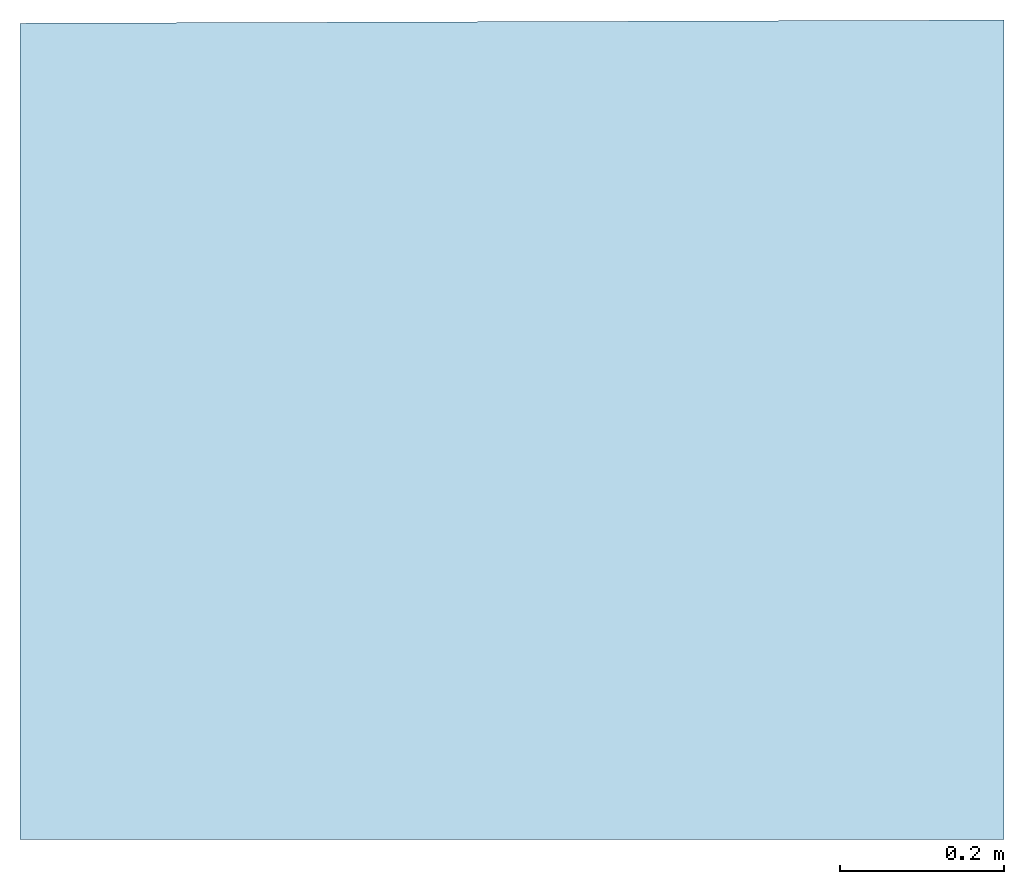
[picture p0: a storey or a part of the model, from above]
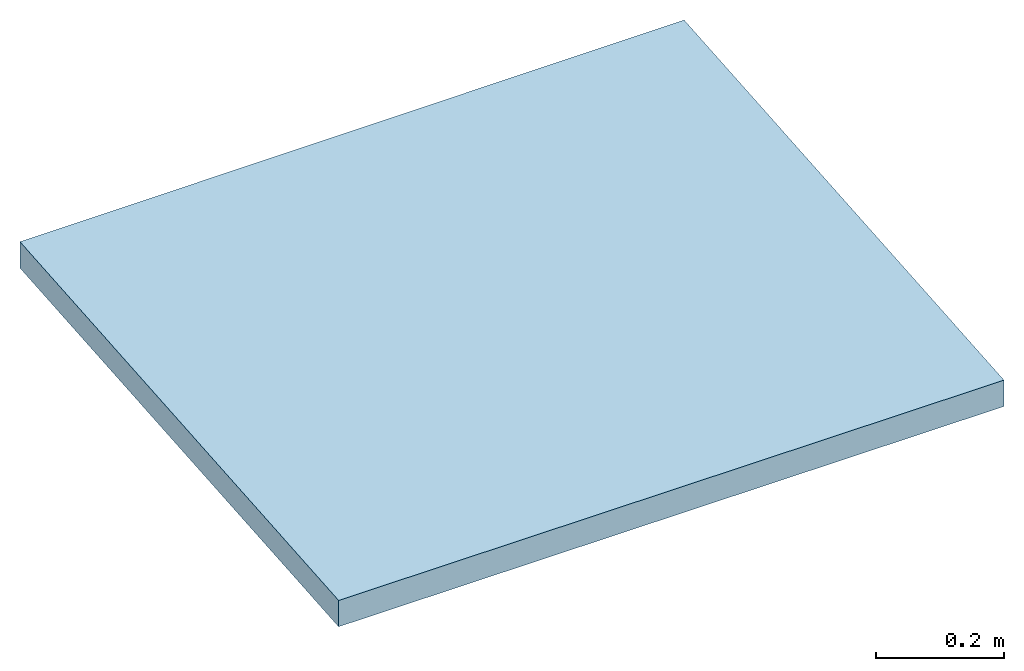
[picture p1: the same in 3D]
Properties of the parts of a building model (IFC2X3)

# File
Description: ViewDefinition [CoordinationView_V2.0], Option [Elements to export: Visible elements (on all stories)], Option [Partial Structure Display: Entire Model], Option [IFC Domain: All], Option [Structural Function: All Elements], Option [Convert Grid elements: On], Option [Convert IFC Annotations and Archicad 2D elements: Off], Option [Convert 2D symbols of Doors and Windows: Off], Option [Export geometries that Participates in Collision Detection only: Off], Option [Split complex elements: Off], Option [Material Preservation: Explode where necessary], Option [Elements in Solid Element Operations: Extruded/revolved], Option [Elements with junctions: Extruded/revolved without junctions], Option [IFC Model position: Survey Point and Project Origin], Option [Curtain Wall export mode: Container Element], Option [Railing export mode: Single Element], Option [Stair export mode: Container Element], Option [Properties To Export: All properties], Option [Space containment: Off], Option [Geometry to type objects: Off], Option [Element Properties: Off], Option [Building Material Properties: Off], Option [Element Parameters: Off], Option [Component Parameters: Off], Option [IFC Base Quantities: Off], Option [Door Window Parameters: On], Option [IFC Space boundaries: Off], Option [Archicad Zone Categories as IFC Space classification data: Off], Option [Element Classifications: Off]
File name: D:\Escritório\Mirela\MINISTERIO DA SAUDE\UBS\UBS PORTE 2\PDF ENTREGA 14.10.24\UBS PORTE 2 - R01.ifc
Time: 2024-10-14T22:08:18
Author: EQUIPE DE ARQUITETURA SAES
Organization: Building Designer Office
Written by: DDS_IFC v3.0
Made in: IFC file generated by Graphisoft Archicad 26.0.0 INT FULL Windows version (IFC add-on version: 4019 INT FULL).
Authorization: EQUIPE DE ARQUITETURA SAES

# IfcProject, UBS - PORTE II
Description: -; Phase: PROJETO EXECUTIVO

# IfcSite, Site
RefLatitude: 24, 28, 0, 0; RefLongitude: 54, 25, 0, 0; RefElevation: 0 mm

# IfcBuildingStorey (4)
In: Building
Name | LongName | Elevation (mm)
TÉRREO | TÉRREO | 150
COBERTURA | COBERTURA | 3650
PLATIBANDA | PLATIBANDA | 5750
NÍVEL DA RUA |  | 0

# IfcBeam: Concreto 200 x 950 (3)
In: PLATIBANDA
Material: Concreto
Pset_BeamCommon - Reference: Viga C-30 - Seção Retangular 20 X 95; IsExternal: yes; LoadBearing: yes
AltoQi_Eberick_Cargas - Cargas de parede (G2): 0; Adicional (G2): 0; Solo (S): 0; Acidental (Q): 0; Água (A): 0; Subpressão (AS): 0
AltoQi_Eberick_Elemento - Elemento: Viga; Tipo: retangular; Seção_bw: 200 mm; Seção_h: 950 mm; Elevação: 0 mm; Taxa de armadura: 0.16 %
AltoQi_Eberick_Padrão - Ambiente: Externo; Cobrimento: 30 mm; Classe de concreto: C-30
AC_Pset_RenovationAndPhasing - Renovation Status: Existing
Pset_ConcreteElementGeneral - EnvironmentalClass: 2; ConstructionType: InSitu

# IfcBeam: Railing Type (80)
In: TÉRREO
AC_Pset_RenovationAndPhasing - Renovation Status: Existing

# IfcBuildingElementPart (341)
In: TÉRREO
Name | Material
8 x Vidro | Vidro
8 x 
8 x _METAL | _METAL
285 x _GRANITO | _GRANITO
20 x _REBOCO | _REBOCO
10 x _ALVENARIA | _ALVENARIA
_PISO | _PISO
_CONCRETO | _CONCRETO

# IfcBuildingElementProxy: Bancada Seca 01 500 x 200 (2)
In: TÉRREO
Material: _GRANITO
AC_Pset_RenovationAndPhasing - Renovation Status: Existing
Name | Description
BPC.200d-Escovodromo | Bancada em granito 2,00x0,50m, com duas cubas cerâmica oval.
BPC.100e-Escovodromo | Bancada em granito 1,00x0,50m, com uma cubas cerâmica oval.

# IfcBuildingElementProxy: Basin 26 (16)
In: TÉRREO
AC_Pset_RenovationAndPhasing - Renovation Status: Existing
Name | Description
15 x LV01 | Lavatório com coluna suspensa em louça, cor branco, com acabamento em coluna suspensa. Incluso válvula de metal cromado e sifão flexível em PVC.
LV.02 | Lavatório Infantil com coluna suspensa em louça, cor branco. Com acabamento em coluna suspensa. Incluso válvula de metal cromado e sifão flexível em PVC.

# IfcBuildingElementProxy: Blocks_Banco Perfurado_F03652PT(2), BC01
In: TÉRREO
Description: Banco articulado nos banheiros adaptados, com estrutura em aço inox, assento em polipropileno na cor branco, fixado na parede com sistema de travamento na vertical, dimensão 70cm x 45cm, com estrutura que suporte até 150kg.
AC_Pset_RenovationAndPhasing - Renovation Status: Existing

# IfcBuildingElementProxy: Fire-Products_Bosch_Sounders (2)
In: TÉRREO
Description: Botão de emergência, item de acessibilidade para banheiros.
AC_Pset_RenovationAndPhasing - Renovation Status: Existing

# IfcBuildingElementProxy: Fire-Products_Bosch_Sounders(3) (4)
In: TÉRREO
Description: Botão de emergência, item de acessibilidade para banheiros.
AC_Pset_RenovationAndPhasing - Renovation Status: Existing

# IfcBuildingElementProxy: Grab Bar 26 (26)
In: TÉRREO
AC_Pset_RenovationAndPhasing - Renovation Status: Existing
Name | Description
10 x BA80 | Barra de apoio, reta, fixa, em aço inox, l=80cm, com diâmetro de empunhadura de 30mm. Deverão ser instaladas nos banheiros PCD como suporte para o uso dos equipamentos.
5 x BA70 | Barra de apoio, reta, fixa, em aço inox, l=70cm, com diâmetro de empunhadura de 30mm. Deverão ser instaladas nos banheiros PCD como suporte para o uso dos equipamentos.
10 x BA40 | Barra de apoio, reta, fixa, em aço inox, l=40cm, com diâmetro de empunhadura de 30mm.
BA60 | Barra de apoio, reta, fixa, em aço inox, l=60cm, com diâmetro de empunhadura de 30mm.

# IfcBuildingElementProxy: Interruptor Elétrico BRA 26 (86)
In: TÉRREO
AC_Pset_RenovationAndPhasing - Renovation Status: Existing

# IfcBuildingElementProxy: Interruptor Elétrico BRA 26(1) (120)
In: TÉRREO
AC_Pset_RenovationAndPhasing - Renovation Status: Existing

# IfcBuildingElementProxy: Rectangular Floor Drain 26 (21)
In: TÉRREO
Description: Ralo sanfonado, dimensões 15 x 15cm com tampa escamoteável.
AC_Pset_RenovationAndPhasing - Renovation Status: Existing

# IfcBuildingElementProxy: Sanitary_Accessories_Cosmic_ARCHITECT-Hinged-Grab-Bar(2), BAR70
In: TÉRREO
Description: Barra de apoio, reta, articulável, em aço inox, l=70cm, com diâmetro de empunhadura de 30mm.
AC_Pset_RenovationAndPhasing - Renovation Status: Existing

# IfcBuildingElementProxy: Tap 26 (27)
In: TÉRREO
Description: Torneira de mesa, acionamento de pressão, acabamento e acessórios para fixação e instalação cromados.
Pset_ManufacturerTypeInformation - Manufacturer: Deca Vogue Plus, L510; ou similar de qualidade igual ou superior
AC_Pset_RenovationAndPhasing - Renovation Status: Existing

# IfcBuildingElementProxy: Various Structures - 2 Segments - 400 x 200 x 100 (80+20), x
In: TÉRREO
Description: Bancada em granito 1,60x0,60m, com uma cuba em inox retangular e uma cuba em cerâmica redonda.
AC_Pset_RenovationAndPhasing - Renovation Status: Existing

# IfcBuildingElementProxy: Various Structures - 2 Segments - 600 x 200 x 1250 (20+1230), X
In: TÉRREO
Description: Bancada em granito 2,50x0,60m, com uma cuba em inox.
AC_Pset_RenovationAndPhasing - Renovation Status: Existing

# IfcBuildingElementProxy: Various Structures - 2 Segments - 600 x 200 x 1500 (20+1480), BPC.160d
In: TÉRREO
Description: Bancada em granito 1,60x0,60m, com uma cuba em inox retangular e uma cuba em cerâmica redonda.
AC_Pset_RenovationAndPhasing - Renovation Status: Existing

# IfcBuildingElementProxy: Various Structures - 3 Segments - 550 x 200 x 1200 (20+500+680), BPC.120e
In: TÉRREO
Description: Bancada em granito 1,20x0,55m, com uma cuba em cerâmica redonda.
AC_Pset_RenovationAndPhasing - Renovation Status: Existing

# IfcBuildingElementProxy: Various Structures - 3 Segments - 550 x 200 x 2200 (20+1200+980) (3)
In: TÉRREO
Description: Bancada em granito 2,20x0,55m, com uma cuba em inox retangular e uma cuba em cerâmica redonda.
AC_Pset_RenovationAndPhasing - Renovation Status: Existing

# IfcBuildingElementProxy: Various Structures - 3 Segments - 550 x 200 x 800 (20+500+280), BPC.80d
In: TÉRREO
Description: Bancada em granito 0,80x0,55m, com uma cuba em cerâmica redonda.
AC_Pset_RenovationAndPhasing - Renovation Status: Existing

# IfcBuildingElementProxy: Various Structures - 3 Segments - 600 x 200 x 1600 (20+1560+20), BPC.160
In: TÉRREO
Description: Bancada em granito 1,60x0,60m, com uma cuba em inox retangular e uma cuba em cerâmica redonda.
AC_Pset_RenovationAndPhasing - Renovation Status: Existing

# IfcBuildingElementProxy: Various Structures - 3 Segments - 600 x 200 x 1800 (20+1760+20), BPC.180e
In: TÉRREO
Description: Bancada em granito 1,80x0,60m, com uma cuba em inox retangular e uma cuba em cerâmica redonda.
AC_Pset_RenovationAndPhasing - Renovation Status: Existing

# IfcBuildingElementProxy: Various Structures - 3 Segments - 750 x 200 x 3151 (20+3111+20), BI.315de
In: TÉRREO
Description: Bancada em L em Inox 3,15 x 2,00m, profundidade 0,60 e 0,75m, sem cuba
AC_Pset_RenovationAndPhasing - Renovation Status: Existing

# IfcBuildingElementProxy: Various Structures - 4 Segments - 600 x 200 x 1800 (20+1056+704+20), BPC.180d
In: TÉRREO
Description: Bancada em granito 1,80x0,60m, com uma cuba retangular em inox.
AC_Pset_RenovationAndPhasing - Renovation Status: Existing

# IfcBuildingElementProxy: Various Structures - 4 Segments - 600 x 200 x 2600 (20+1280+1280+20), BIC.260d
In: TÉRREO
Description: Bancada em Inox 2,60x0,60m, com uma cuba retangular em inox.
AC_Pset_RenovationAndPhasing - Renovation Status: Existing

# IfcBuildingElementProxy: WC Disabled 26 (7)
In: TÉRREO
Description: Bacia sanitária c/caixa de descarga acoplada, na cor branco, inclusive assento na cor branco, contendo conjunto de fixação, anel de vedação e engate plástico.
AC_Pset_RenovationAndPhasing - Renovation Status: Existing

# IfcBuildingElementProxy: _GRANITO 20 x 120, x
In: TÉRREO
Description: Bancada em granito 1,60x0,60m, com uma cuba em inox retangular e uma cuba em cerâmica redonda.; Material: _GRANITO
AC_Pset_RenovationAndPhasing - Renovation Status: Existing

# IfcBuildingElementProxy: cuba embutir_mekal_CR30 (8)
In: TÉRREO
Description: Cuba de embutir redonda em louça, cor branco, dimensão de 36cm ou equivalente. Incluso válvula de metal cromado e sifão flexível em PVC.
AC_Pset_RenovationAndPhasing - Renovation Status: Existing

# IfcBuildingElementProxy: ducha higienica_link_deca_1984.C.ACT.LNK.CR(1) (6)
In: TÉRREO
Description: Ducha higiênica com registro.
AC_Pset_RenovationAndPhasing - Renovation Status: Existing

# IfcBuildingElementProxy: ducha higienica_link_deca_1984.C.ACT.LNK.CR(3), DC01
In: TÉRREO
Description: Ducha higiênica com registro.
AC_Pset_RenovationAndPhasing - Renovation Status: Existing

# IfcColumn: Various Structures - 8 Segments - 3000 x 3000 x 8800 (1200+1200+1200+1200+1200+1200+1200+400), Reservatório de água
In: TÉRREO
AC_Pset_RenovationAndPhasing - Renovation Status: Existing
Pset_ColumnCommon - Reference: Various Structures - 8 Segments - 3000 x 3000 x 8800 (1200+1200+1200+1200+1200+1200+1200+400)

# IfcDiscreteAccessory: Gutter 26 (7)
In: COBERTURA
AC_Pset_RenovationAndPhasing - Renovation Status: Existing
Name
Calha 02
Calha 05
2 x Calha 04
2 x Calha 01
Calha 03

# IfcDiscreteAccessory: Text 3D 26 (2)
In: TÉRREO
Description: Mesa tipo escrivaninha
AC_Pset_RenovationAndPhasing - Renovation Status: Existing

# IfcDistributionElement: Shower Kit 26 (3)
In: TÉRREO
Description: Chuveiro Elétrico - 220V
AC_Pset_RenovationAndPhasing - Renovation Status: Existing

# IfcDistributionElement: Tanque de Lavar Roupa, T.Q.
In: TÉRREO
Description: Tanque em louças com coluna na cor branca
AC_Pset_RenovationAndPhasing - Renovation Status: Existing

# IfcDistributionElement: Tap 26 (8)
In: TÉRREO
Description: Torneira de cotovelo para bancada com acabamento e acessórios de fixação e instalação cromados
AC_Pset_RenovationAndPhasing - Renovation Status: Existing

# IfcDistributionElement: Wall Mounted Tap 26 (7)
In: TÉRREO
AC_Pset_RenovationAndPhasing - Renovation Status: Existing
Name | Description
Lavatório 01 | Torneira banheiro extensível bica alta, monocomando. Água quente | Pset_ManufacturerTypeInformation - Manufacturer: Deca Vogue Plus, L510; ou similar de qualidade igual ou superior
Lavatório 01 | Torneira de parede, alavanca longa, acionamento pelo cotovelo, para tanque com acabamento e acessórios para fixação e instalação cromados | Pset_ManufacturerTypeInformation - Manufacturer: Deca Vogue Plus, L510; ou similar de qualidade igual ou superior
5 x T.PD.03 | Torneira para Jardim Bica Baixa com adaptador para mangueira

# IfcDistributionElement: Washer 26, LV
In: TÉRREO
AC_Pset_RenovationAndPhasing - Renovation Status: Existing

# IfcDoor: Door 26 (11)
In: TÉRREO
Type - OperationType: SINGLE_SWING_LEFT; ParameterTakesPrecedence: no; Sizeable: no
Type - Door Lining Properties - LiningThickness: 50 mm; CasingThickness: 50 mm; CasingDepth: 19 mm
Type - Door Panel Properties - Panel 1 - PanelDepth: 40 mm; PanelOperation: SWINGING; PanelWidth: 1; PanelPosition: MIDDLE
OverallHeight: 2150 mm
AC_Pset_RenovationAndPhasing - Renovation Status: Existing
Name | Description | OverallWidth (mm)
5 x PA80 | Porta de madeira, 1 folha abertura de giro, com acabamento em pintura branca | 900
4 x PA90a | Porta de madeira, 1 folha abertura de giro, com acabamento em pintura branca | 1000
PA120a-A | Porta de alumínio anodizado 1 folhas, abertura de giro, com acabamento em pintura branca | 1300
PA90b | Porta de madeira, 1 folha abertura de giro, com acabamento em pintura branca | 1000

# IfcDoor: Door 26, PA80a-Guichê
In: TÉRREO
Type - OperationType: SINGLE_SWING_LEFT; ParameterTakesPrecedence: no; Sizeable: no
Type - Door Lining Properties - LiningThickness: 50 mm; ThresholdDepth: 300 mm; ThresholdThickness: 12 mm; ThresholdOffset: 0 mm; CasingThickness: 50 mm; CasingDepth: 19 mm
Type - Door Panel Properties - Panel 1 - PanelDepth: 40 mm; PanelOperation: SWINGING; PanelWidth: 1; PanelPosition: MIDDLE
Description: Porta de madeira, 1 folha abertura de giro, com acabamento em pintura branca; OverallHeight: 2150 mm; OverallWidth: 900 mm
AC_Pset_RenovationAndPhasing - Renovation Status: Existing

# IfcDoor: Door 26 (3)
In: TÉRREO
Type - OperationType: SINGLE_SWING_LEFT; ParameterTakesPrecedence: no; Sizeable: no
Type - Door Lining Properties - LiningThickness: 50 mm
Type - Door Panel Properties - Panel 1 - PanelDepth: 35 mm; PanelOperation: SWINGING; PanelWidth: 1; PanelPosition: MIDDLE
Description: Porta de giro, alumínio anodizado tipo lambril, cor branca; OverallHeight: 2150 mm; OverallWidth: 1000 mm
AC_Pset_RenovationAndPhasing - Renovation Status: Existing

# IfcDoor: Door 26 (15)
In: TÉRREO
Type - OperationType: SINGLE_SWING_RIGHT; ParameterTakesPrecedence: no; Sizeable: no
Type - Door Lining Properties - LiningThickness: 50 mm; CasingThickness: 50 mm; CasingDepth: 19 mm
Type - Door Panel Properties - Panel 1 - PanelDepth: 40 mm; PanelOperation: SWINGING; PanelWidth: 1; PanelPosition: MIDDLE
OverallHeight: 2150 mm
AC_Pset_RenovationAndPhasing - Renovation Status: Existing
Name | Description | OverallWidth (mm)
PA120a | Porta de madeira com vidro, 1 folha abertura de giro, com acabamento em pintura branca | 1300
8 x PA90a | Porta de madeira, 1 folha abertura de giro, com acabamento em pintura branca | 1000
6 x PA80 | Porta de madeira, 1 folha abertura de giro, com acabamento em pintura branca | 900

# IfcDoor: Double Door 26 (3)
In: TÉRREO
Type - OperationType: DOUBLE_DOOR_SINGLE_SWING; ParameterTakesPrecedence: no; Sizeable: no
Type - Door Lining Properties - LiningThickness: 30 mm
Type - Door Panel Properties - Panel 1 - PanelDepth: 30 mm; PanelOperation: SWINGING; PanelWidth: 0.5; PanelPosition: LEFT
Type - Door Panel Properties - Panel 2 - PanelDepth: 30 mm; PanelOperation: SWINGING; PanelWidth: 0.5; PanelPosition: RIGHT
Description: Porta de alumínio com tela de giro, 2 folhas, acabamento em pintura branca; OverallHeight: 1300 mm; OverallWidth: 1000 mm
AC_Pset_RenovationAndPhasing - Renovation Status: Existing

# IfcDoor: Double Door 26 (3)
In: TÉRREO
Type - OperationType: DOUBLE_DOOR_SINGLE_SWING; ParameterTakesPrecedence: no; Sizeable: no
Type - Door Lining Properties - LiningThickness: 30 mm
Type - Door Panel Properties - Panel 1 - PanelDepth: 30 mm; PanelOperation: SWINGING; PanelWidth: 0.5; PanelPosition: RIGHT
Type - Door Panel Properties - Panel 2 - PanelDepth: 30 mm; PanelOperation: SWINGING; PanelWidth: 0.5; PanelPosition: LEFT
Description: Porta de alumínio com tela de giro, 2 folhas, acabamento em pintura branca
AC_Pset_RenovationAndPhasing - Renovation Status: Existing
Name | OverallHeight (mm) | OverallWidth (mm)
PF1 | 1800 | 1500
2 x PF2 | 1300 | 1000

# IfcDoor: Double Door 26, PORTÃO
In: TÉRREO
Type - OperationType: DOUBLE_DOOR_SINGLE_SWING; ParameterTakesPrecedence: no; Sizeable: no
Type - Door Lining Properties - LiningThickness: 50 mm; CasingThickness: 50 mm; CasingDepth: 19 mm
Type - Door Panel Properties - Panel 1 - PanelDepth: 40 mm; PanelOperation: SWINGING; PanelWidth: 0.5; PanelPosition: LEFT
Type - Door Panel Properties - Panel 2 - PanelDepth: 40 mm; PanelOperation: SWINGING; PanelWidth: 0.5; PanelPosition: RIGHT
Description: Portão em alumínio de giro, 2 folhas, acabamento em pintura branca; OverallHeight: 2500 mm; OverallWidth: 4100 mm
AC_Pset_RenovationAndPhasing - Renovation Status: Existing

# IfcDoor: Double Door 26, PAD160
In: TÉRREO
Type - OperationType: DOUBLE_DOOR_SINGLE_SWING; ParameterTakesPrecedence: no; Sizeable: no
Type - Door Lining Properties - LiningThickness: 50 mm; CasingThickness: 50 mm; CasingDepth: 19 mm
Type - Door Panel Properties - Panel 1 - PanelDepth: 40 mm; PanelOperation: SWINGING; PanelWidth: 0.50625; PanelPosition: LEFT
Type - Door Panel Properties - Panel 2 - PanelDepth: 40 mm; PanelOperation: SWINGING; PanelWidth: 0.50625; PanelPosition: RIGHT
Description: Porta de madeira, 2 folhas, abertura de giro, com acabamento em pintura branca.; OverallHeight: 2150 mm; OverallWidth: 1700 mm
AC_Pset_RenovationAndPhasing - Renovation Status: Existing

# IfcDoor: Double Door 26, PAD160
In: TÉRREO
Type - OperationType: DOUBLE_DOOR_SINGLE_SWING; ParameterTakesPrecedence: no; Sizeable: no
Type - Door Lining Properties - LiningThickness: 50 mm; CasingThickness: 50 mm; CasingDepth: 19 mm
Type - Door Panel Properties - Panel 1 - PanelDepth: 40 mm; PanelOperation: SWINGING; PanelWidth: 0.50625; PanelPosition: RIGHT
Type - Door Panel Properties - Panel 2 - PanelDepth: 40 mm; PanelOperation: SWINGING; PanelWidth: 0.50625; PanelPosition: LEFT
Description: Porta de madeira, 2 folhas, abertura de giro, com acabamento em pintura branca.; OverallHeight: 2150 mm; OverallWidth: 1700 mm
AC_Pset_RenovationAndPhasing - Renovation Status: Existing

# IfcDoor: Double Door 26, PAD200a-A
In: TÉRREO
Type - OperationType: DOUBLE_DOOR_SINGLE_SWING; ParameterTakesPrecedence: no; Sizeable: no
Type - Door Lining Properties - LiningThickness: 50 mm; CasingThickness: 50 mm; CasingDepth: 19 mm
Type - Door Panel Properties - Panel 1 - PanelDepth: 40 mm; PanelOperation: SWINGING; PanelWidth: 0.506316; PanelPosition: LEFT
Type - Door Panel Properties - Panel 2 - PanelDepth: 40 mm; PanelOperation: SWINGING; PanelWidth: 0.506316; PanelPosition: RIGHT
Description: Porta de alumínio anodizado com vidro, 2 folhas, abertura de giro, com acabamento em pintura branca; OverallHeight: 2150 mm; OverallWidth: 2000 mm
AC_Pset_RenovationAndPhasing - Renovation Status: Existing

# IfcDoor: Double Door 26, PAD200a-A
In: TÉRREO
Type - OperationType: DOUBLE_DOOR_SINGLE_SWING; ParameterTakesPrecedence: no; Sizeable: no
Type - Door Lining Properties - LiningThickness: 50 mm; CasingThickness: 50 mm; CasingDepth: 19 mm
Type - Door Panel Properties - Panel 1 - PanelDepth: 40 mm; PanelOperation: SWINGING; PanelWidth: 0.506316; PanelPosition: RIGHT
Type - Door Panel Properties - Panel 2 - PanelDepth: 40 mm; PanelOperation: SWINGING; PanelWidth: 0.506316; PanelPosition: LEFT
Description: Porta de alumínio anodizado com vidro, 2 folhas, abertura de giro, com acabamento em pintura branca; OverallHeight: 2150 mm; OverallWidth: 2000 mm
AC_Pset_RenovationAndPhasing - Renovation Status: Existing

# IfcDoor: Double Door 26 (2)
In: TÉRREO
Type - OperationType: DOUBLE_DOOR_SINGLE_SWING; ParameterTakesPrecedence: no; Sizeable: no
Type - Door Lining Properties - LiningThickness: 50 mm; CasingThickness: 50 mm; CasingDepth: 19 mm
Type - Door Panel Properties - Panel 1 - PanelDepth: 40 mm; PanelOperation: SWINGING; PanelWidth: 0.506667; PanelPosition: RIGHT
Type - Door Panel Properties - Panel 2 - PanelDepth: 40 mm; PanelOperation: SWINGING; PanelWidth: 0.506667; PanelPosition: LEFT
Description: Porta de alumínio com vidro, 2 folhas, abertura de giro, com acabamento em pintura branca; OverallHeight: 2600 mm; OverallWidth: 1600 mm
AC_Pset_RenovationAndPhasing - Renovation Status: Existing

# IfcDoor: Double Door 26 (4)
In: TÉRREO
Type - OperationType: DOUBLE_DOOR_SINGLE_SWING; ParameterTakesPrecedence: no; Sizeable: no
Type - Door Lining Properties - LiningThickness: 50 mm; CasingThickness: 50 mm; CasingDepth: 19 mm
Type - Door Panel Properties - Panel 1 - PanelDepth: 40 mm; PanelOperation: SWINGING; PanelWidth: 0.51; PanelPosition: LEFT
Type - Door Panel Properties - Panel 2 - PanelDepth: 40 mm; PanelOperation: SWINGING; PanelWidth: 0.51; PanelPosition: RIGHT
Description: Porta de alumínio anodizado com vidro, 2 folhas, abertura de giro, com acabamento em pintura branca; OverallHeight: 2150 mm; OverallWidth: 1300 mm
AC_Pset_RenovationAndPhasing - Renovation Status: Existing

# IfcDoor: Double Door 26, PAD150a-A
In: TÉRREO
Type - OperationType: DOUBLE_DOOR_SINGLE_SWING; ParameterTakesPrecedence: no; Sizeable: no
Type - Door Lining Properties - LiningThickness: 50 mm
Type - Door Panel Properties - Panel 1 - PanelDepth: 35 mm; PanelOperation: SWINGING; PanelWidth: 0.506667; PanelPosition: RIGHT
Type - Door Panel Properties - Panel 2 - PanelDepth: 35 mm; PanelOperation: SWINGING; PanelWidth: 0.506667; PanelPosition: LEFT
Description: Porta corta fogo, 2 folhas, abertura de giro, com acabamento em pintura branca; OverallHeight: 2150 mm; OverallWidth: 1600 mm
AC_Pset_RenovationAndPhasing - Renovation Status: Existing

# IfcDoor: Double Door 26, PAD110a-A
In: TÉRREO
Type - OperationType: DOUBLE_DOOR_SINGLE_SWING; ParameterTakesPrecedence: no; Sizeable: no
Type - Door Lining Properties - LiningThickness: 50 mm
Type - Door Panel Properties - Panel 1 - PanelDepth: 35 mm; PanelOperation: SWINGING; PanelWidth: 0.509091; PanelPosition: LEFT
Type - Door Panel Properties - Panel 2 - PanelDepth: 35 mm; PanelOperation: SWINGING; PanelWidth: 0.509091; PanelPosition: RIGHT
Description: Porta de alumínio anodizado, com veneziana, 2 folhas, abertura de giro, com acabamento em pintura branca; OverallHeight: 2150 mm; OverallWidth: 1200 mm
AC_Pset_RenovationAndPhasing - Renovation Status: Existing

# IfcDoor: Double Door 26 (2)
In: TÉRREO
Type - OperationType: DOUBLE_DOOR_SINGLE_SWING; ParameterTakesPrecedence: no; Sizeable: no
Type - Door Lining Properties - LiningThickness: 50 mm
Type - Door Panel Properties - Panel 1 - PanelDepth: 35 mm; PanelOperation: SWINGING; PanelWidth: 0.509091; PanelPosition: RIGHT
Type - Door Panel Properties - Panel 2 - PanelDepth: 35 mm; PanelOperation: SWINGING; PanelWidth: 0.509091; PanelPosition: LEFT
Description: Porta de alumínio anodizado, com veneziana, 2 folhas, abertura de giro, com acabamento em pintura branca; OverallHeight: 2150 mm; OverallWidth: 1200 mm
AC_Pset_RenovationAndPhasing - Renovation Status: Existing

# IfcDoor: Exterior Sliding Door 26 (5)
In: TÉRREO
Type - OperationType: SLIDING_TO_LEFT; ParameterTakesPrecedence: no; Sizeable: no
Type - Door Lining Properties - CasingThickness: 50 mm; CasingDepth: 18 mm
Type - Door Panel Properties - Panel 1 - PanelDepth: 35 mm; PanelOperation: SLIDING; PanelWidth: 1; PanelPosition: MIDDLE
Description: Porta de madeira, 1 folha, com abertura de correr, acabamento em pintura branca; OverallHeight: 2150 mm; OverallWidth: 1050 mm
AC_Pset_RenovationAndPhasing - Renovation Status: Existing
Name
2 x PC90b
2 x PC90a
PC90a-A

# IfcDoor: Exterior Sliding Door 26 (4)
In: TÉRREO
Type - OperationType: SLIDING_TO_RIGHT; ParameterTakesPrecedence: no; Sizeable: no
Type - Door Lining Properties - CasingThickness: 50 mm; CasingDepth: 18 mm
Type - Door Panel Properties - Panel 1 - PanelDepth: 35 mm; PanelOperation: SLIDING; PanelWidth: 1; PanelPosition: MIDDLE
Description: Porta de madeira, 1 folha, com abertura de correr, acabamento em pintura branca; OverallHeight: 2150 mm; OverallWidth: 1050 mm
AC_Pset_RenovationAndPhasing - Renovation Status: Existing
Name
3 x PC90a
PC90b

# IfcDoor: Sliding Door 26 (2)
In: TÉRREO
Type - OperationType: USERDEFINED; ParameterTakesPrecedence: no; Sizeable: no
Description: Caixilho tipo Box, estrutura em alumínio na cor branca, duas folhas de vidro temperado, transparente; OverallHeight: 1900 mm; OverallWidth: 1250 mm
AC_Pset_RenovationAndPhasing - Renovation Status: New

# IfcEnergyConversionDevice: Interruptor Elétrico BRA 26 (6)
In: TÉRREO
AC_Pset_RenovationAndPhasing - Renovation Status: Existing

# IfcFlowTerminal: Fluorescent Lamp 26 (130)
In: TÉRREO
AC_Pset_RenovationAndPhasing - Renovation Status: Existing
Name | Description
6 x LM04 | Luminária de sobrepor de LED quadrado, dimensão de 20 x 20cm ou equivalente. Corpo fabricado em alumínio com acabamento em pintura eletrostática na cor branco ou similar. Montada com LED integrado de alta performance 19W branco neutro ou branco frio 4500k - 6500K e driver bivolt.
53 x LM02 | Luminária de embutir de LED quadrado, dimensão de 40 x 40cm ou equivalente. Corpo fabricado em alumínio com acabamento em pintura eletrostática na cor branco ou similar. Montada com LED integrado de alta performance 36W branco neutro ou branco frio 4500k - 6500K e driver bivolt.
14 x LM01 | Luminária de embutir de LED quadrado, dimensão de 20 x 20cm ou equivalente. Corpo fabricado em alumínio com acabamento em pintura eletrostática na cor branco ou similar. Fixada através de presilhas para gesso. Montada com LED integrado de alta performance 19W branco neutro ou branco frio 4500k - 6500K e driver bivolt.
26 x LM05 | Luminária de embutir de LED quadrado, dimensão de 60 x 60cm ou equivalente. Corpo fabricado em alumínio com acabamento em pintura eletrostática na cor branco ou similar. Montada com LED integrado de alta performance 40W branco neutro ou branco frio 4500k - 6500K e driver bivolt.
31 x Iluminação de Emergência | Bloco autônomo ilum. emergência na parede

# IfcFlowTerminal: Spotlamp Ground 26 (8)
In: TÉRREO
Description: Luminária de piso. Corpo fabricado em alumínio com acabamento em pintura eletrostática na cor branca. Montada com LED integrado de alta performance 7W neutra 4000K e driver bivolt.
AC_Pset_RenovationAndPhasing - Renovation Status: Existing

# IfcFlowTerminal: Wall Lamp 26 (46)
In: TÉRREO
AC_Pset_RenovationAndPhasing - Renovation Status: Existing
Name | Description
24 x LM06 | Luminária tipo arandela quadrada. Corpo fabricado em alumínio com acabamento em pintura eletrostática na cor branca. Montada com LED integrado de alta performance 6W neutra 4000K e driver bivolt.
22 x LM03 | Luminária de sobrepor tipo arandela tartaruga. Corpo fabricado em alumínio com acabamento em pintura eletrostática na cor branca. Montada com LED integrado de alta performance 24W neutra 4000K e driver bivolt.

# IfcFurnishingElement: Alumínio 100 x 150 (15)
In: TÉRREO
Description: VIGA BALDRAME 45cm; Material: Alumínio
AC_Pset_RenovationAndPhasing - Renovation Status: Existing

# IfcFurnishingElement: Cuba deca Oval 40x30 (3)
In: TÉRREO
Description: Cuba de embutir oval em louça, cor branco, dimensão de 40 x 30cm ou equivalente. Incluso válvula de metal cromado e sifão flexível em PVC.; Material: Solid Fill 332912669
AC_Pset_RenovationAndPhasing - Renovation Status: Existing

# IfcFurnishingElement: Dental Chair 26 (3)
In: TÉRREO
Description: Conjunto equipo, cadeira e acessórios existente a manter
AC_Pset_RenovationAndPhasing - Renovation Status: Existing

# IfcFurnishingElement: Filtro de agua eletrolux (3)
In: TÉRREO
Description: Purificador de água.
AC_Pset_RenovationAndPhasing - Renovation Status: Existing

# IfcFurnishingElement: LEM_cuba tramontina 400x340x140 (8)
In: TÉRREO
Description: Cuba retangular, em aço inox, dimensão de 40x34cm ou equivalente.Incluso válvula de metal cromado e sifão flexível em PVC.
AC_Pset_RenovationAndPhasing - Renovation Status: Existing

# IfcFurnishingElement: LOGO SUS SKT proporcional (2)
In: COBERTURA
Description: Leito/Cama
AC_Pset_RenovationAndPhasing - Renovation Status: Existing

# IfcFurnishingElement: Microwave Oven 26 (2)
In: TÉRREO
AC_Pset_RenovationAndPhasing - Renovation Status: Existing
Name
MB.MC01 | Description: Microondas
Autoclave 65L

# IfcFurnishingElement: Refrigerator 26 (5)
In: TÉRREO
AC_Pset_RenovationAndPhasing - Renovation Status: Existing
Name | Description
Geladeira Vacinas | Geladeira para vacinas
Geladeira
2 x Geladeira Termolábeis | Geladeira para vacinas
Freezer | Freezer com termômetro

# IfcFurnishingElement: Rufo Metálico 155 x 50 (14)
In: COBERTURA
Description: VIGA BALDRAME 45cm; Material: _GRANILITE
AC_Pset_RenovationAndPhasing - Renovation Status: Existing

# IfcFurnishingElement: Rufo Metálico Central 10% 200 x 15 (3)
In: COBERTURA
Description: VIGA BALDRAME 45cm; Material: _GRANILITE
AC_Pset_RenovationAndPhasing - Renovation Status: Existing

# IfcFurnishingElement: Solar Photovoltaic Panel 26 (62)
In: COBERTURA
Description: Mesa tipo escrivaninha
AC_Pset_RenovationAndPhasing - Renovation Status: Existing

# IfcFurnishingElement: WC 26, VS02
In: TÉRREO
Description: Bacia sanitária infantil com caixa de descarga acoplada, na cor branco, inclusive assento na cor branco, contendo conjunto de fixação, anel de vedação e engate plástico.
AC_Pset_RenovationAndPhasing - Renovation Status: Existing

# IfcSlab: ASFALTO 50, PISO INTERTRAVADO (VIAS INTERNAS E ESTACIONAMENTO)
In: TÉRREO
Type - PredefinedType: FLOOR
Material: ASFALTO 50 mm
AC_Pset_RenovationAndPhasing - Renovation Status: Existing

# IfcSlab: CC_Laje 150 (3)
In: COBERTURA
Type - PredefinedType: FLOOR
Material: _CONCRETO 150 mm
AC_Pset_RenovationAndPhasing - Renovation Status: Existing
Name
2 x Laje Impermeabilizada
LAJE COBERTURA

# IfcSlab: CC_Laje+Acabamento 10cm 150 (6)
In: TÉRREO
Type - PredefinedType: FLOOR
AC_Pset_RenovationAndPhasing - Renovation Status: Existing
Name | Material
5 x PISO EM CONCRETO DESEMPOLADO (PISO EXTERNO) | _PISO 50 mm, _CONCRETO 100 mm
PISO EM CONCRETO DESEMPOLADO (PISO EXTERNO)

# IfcSlab: CONTRAPISO DESEMPOLADO + PISO 110 (8)
In: TÉRREO
Type - PredefinedType: FLOOR
Material: _GRANILITE 10 mm, _CONTRAPISO 100 mm
AC_Pset_RenovationAndPhasing - Renovation Status: Existing
Name
7 x PISO EM GRANILITE SEM POLIDO (PISO INTERNO)
PISO EM GRANILITE POLIDO (PISO INTERNO)

# IfcSlab: GRAMA 50 (4)
In: TÉRREO
Type - PredefinedType: FLOOR
Material: GRAMA 50 mm
AC_Pset_RenovationAndPhasing - Renovation Status: Existing

# IfcSlab: _CONTRAPISO, PISO EM CONCRETO DESEMPOLADO (PISO EXTERNO)
In: TÉRREO
Type - PredefinedType: FLOOR
Material: _CONTRAPISO
AC_Pset_RenovationAndPhasing - Renovation Status: Existing

# IfcSlab: _CONTRAPISO 30 (6)
In: COBERTURA
Type - PredefinedType: ROOF
Description: Inclinação: i=15%; Material: _CONTRAPISO 30 mm
AC_Pset_RenovationAndPhasing - Renovation Status: Existing

# IfcSlab: _CONTRAPISO 50 (4)
Type - PredefinedType: ROOF
Description: Inclinação: i=15%; Material: _CONTRAPISO 50 mm
AC_Pset_RenovationAndPhasing - Renovation Status: Existing
Name | In
PISO EM CONCRETO DESEMPOLADO (PISO EXTERNO) | NÍVEL DA RUA
3 x Telha em Fibrocimento | TÉRREO

# IfcSlab: _GESSO 10 (38)
In: TÉRREO
Type - PredefinedType: FLOOR
Material: _GESSO 10 mm
AC_Pset_RenovationAndPhasing - Renovation Status: Existing

# IfcSlab: _GESSO 600 (2)
In: COBERTURA
Type - PredefinedType: FLOOR
Material: _GESSO 600 mm
AC_Pset_RenovationAndPhasing - Renovation Status: Existing

# IfcSlab: _GRANITO 120, Banco
In: TÉRREO
Type - PredefinedType: FLOOR
Material: _GRANITO 120 mm
AC_Pset_RenovationAndPhasing - Renovation Status: Existing

# IfcSlab: _PISO 50 (7)
In: TÉRREO
Type - PredefinedType: FLOOR
Material: _PISO 50 mm
AC_Pset_RenovationAndPhasing - Renovation Status: Existing

# IfcSlab: _VIDRO AUTOPORTANTE 20, Telha em Policarbonato Transparente
In: TÉRREO
Type - PredefinedType: ROOF
Description: Inclinação: i=15%; Material: _VIDRO AUTOPORTANTE 19.996 mm
AC_Pset_RenovationAndPhasing - Renovation Status: Existing

# IfcWall: DV_ 3 cm Preenchido 30, Divisória em alumínio
In: TÉRREO
Material: Solid Fill 269295175
AC_Pset_RenovationAndPhasing - Renovation Status: Existing

# IfcWall: _P15 _ 2,5 - 10 - 2,5 150 (2)
In: TÉRREO
AC_Pset_RenovationAndPhasing - Renovation Status: Existing

# IfcWall: _P20 _3 - 14 - 3 200 (8)
In: TÉRREO
AC_Pset_RenovationAndPhasing - Renovation Status: Existing

# IfcWallStandardCase: D100_KNAUF 100 (8)
In: TÉRREO
Material: _GESSO 20 mm, _DRYWALL 60 mm, _GESSO 20 mm
AC_Pset_RenovationAndPhasing - Renovation Status: Existing

# IfcWallStandardCase: D100_KNAUF RU 100 (32)
In: TÉRREO
Material: _GESSO 20 mm, _DRYWALL RU 60 mm, _GESSO 20 mm
AC_Pset_RenovationAndPhasing - Renovation Status: Existing

# IfcWallStandardCase: D100_KNAUF RU COM LÃO DE ROCHA 100 (10)
In: TÉRREO
Material: _DRYWALL RU 20 mm, LÃ DE ROCHA EM RU 60 mm, _DRYWALL RU 20 mm
AC_Pset_RenovationAndPhasing - Renovation Status: Existing
Name
2 x Paredes em Drywall RU
8 x Paredes em Drywall RU com lã de vidro

# IfcWallStandardCase: D100_KNAUF ST COM LÃO DE ROCHA 100 (13)
In: TÉRREO
Material: _GESSO 20 mm, LÃ DE ROCHA 60 mm, _GESSO 20 mm
AC_Pset_RenovationAndPhasing - Renovation Status: Existing

# IfcWallStandardCase: _CONTRAPISO 50 (2)
In: TÉRREO
Material: _CONTRAPISO 50 mm
AC_Pset_RenovationAndPhasing - Renovation Status: Existing

# IfcWallStandardCase: _GESSO 30 (2)
In: TÉRREO
Material: _GESSO 30 mm
AC_Pset_RenovationAndPhasing - Renovation Status: New

# IfcWallStandardCase: _P12 _ 1,5 - 9 - 1,5 130 (2)
In: TÉRREO
Material: _REBOCO 30 mm, _ALVENARIA 70 mm, _REBOCO 30 mm
AC_Pset_RenovationAndPhasing - Renovation Status: Existing

# IfcWallStandardCase: _P15 _ 2,5 - 10 - 2,5 150, Parede alvenaria 15cm
In: TÉRREO
Material: _REBOCO 25 mm, _ALVENARIA 100 mm, _REBOCO 25 mm
AC_Pset_RenovationAndPhasing - Renovation Status: Existing

# IfcWallStandardCase: _P20 _3 - 14 - 3 200 (68)
Material: _REBOCO 30 mm, _ALVENARIA 140 mm, _REBOCO 30 mm
AC_Pset_RenovationAndPhasing - Renovation Status: Existing
Name | In
51 x Parede alvenaria 20cm | TÉRREO
3 x Parede alvenaria 20cm (muro externo) | TÉRREO
14 x Parede alvenaria 20cm | COBERTURA

# IfcWindow: 2-Sash Sliding Window 26 (4)
In: TÉRREO
Type - OperationType: DOUBLE_PANEL_VERTICAL; ParameterTakesPrecedence: no; Sizeable: no
Type - Window Lining Properties - LiningDepth: 80 mm; LiningThickness: 40 mm
Description: Janela de alumínio anodizado branco, abertura tipo de correr, 2 folhas.; OverallHeight: 600 mm; OverallWidth: 1200 mm
Pset_WindowCommon - ThermalTransmittance: 0; GlazingAreaFraction: 0.44
AC_Pset_RenovationAndPhasing - Renovation Status: Existing

# IfcWindow: 4-Sash Sliding Window 26 (9)
In: TÉRREO
Type - OperationType: USERDEFINED; ParameterTakesPrecedence: no; Sizeable: no
Type - Window Panel Properties - Panel 1 - OperationType: TOPHUNG; PanelPosition: LEFT; FrameDepth: 40 mm; FrameThickness: 40 mm
Type - Window Panel Properties - Panel 2 - OperationType: TOPHUNG; PanelPosition: RIGHT; FrameDepth: 40 mm; FrameThickness: 40 mm
Description: Janela de alumínio anodizado branco, abertura tipo de correr, 4 folhas.
Pset_WindowCommon - ThermalTransmittance: 0
AC_Pset_RenovationAndPhasing - Renovation Status: Existing
Name | OverallHeight (mm) | OverallWidth (mm) | GlazingAreaFraction
3 x JC220a-A | 600 | 2200 | 0.7812
JC220a-A | 600 | 2200 | 0.8272
4 x JC250b-A | 600 | 2500 | 0.9592
JC250a-A | 900 | 2500 | 1.6132

# IfcWindow: 4-Sash Sliding Window 26 (10)
In: TÉRREO
Type - OperationType: USERDEFINED; ParameterTakesPrecedence: no; Sizeable: no
Type - Window Panel Properties - Panel 1 - OperationType: TOPHUNG; PanelPosition: RIGHT; FrameDepth: 40 mm; FrameThickness: 40 mm
Type - Window Panel Properties - Panel 2 - OperationType: TOPHUNG; PanelPosition: LEFT; FrameDepth: 40 mm; FrameThickness: 40 mm
Description: Janela de alumínio anodizado branco, abertura tipo de correr, 4 folhas.
Pset_WindowCommon - ThermalTransmittance: 0
AC_Pset_RenovationAndPhasing - Renovation Status: Existing
Name | OverallHeight (mm) | OverallWidth (mm) | GlazingAreaFraction
7 x JC250b-A | 600 | 2500 | 0.9592
JC250a-A | 900 | 2500 | 1.6132
2 x JC200 | 900 | 2000 | 1.2432

# IfcWindow: Cobogó 26 (3)
In: TÉRREO
Type - OperationType: USERDEFINED; ParameterTakesPrecedence: no; Sizeable: no
Description: Cobogó Bandeira 30x30cm
AC_Pset_RenovationAndPhasing - Renovation Status: Existing
Name | OverallHeight (mm) | OverallWidth (mm)
C3 | 4170 | 9300
C2 | 4000 | 17442.3
C1 | 3500 | 8298.32

# IfcWindow: Horizontal Multi-Sash Window 26 (6)
In: TÉRREO
Type - OperationType: SINGLE_PANEL; ParameterTakesPrecedence: no; Sizeable: no
Type - Window Lining Properties - LiningDepth: 60 mm; LiningThickness: 40 mm
Type - Window Panel Properties - Panel 1 - OperationType: TOPHUNG; PanelPosition: MIDDLE; FrameDepth: 40 mm; FrameThickness: 40 mm
Description: Janela de alumínio anodizado branco, abertura tipo maxim-ar, 1 folha.; OverallHeight: 600 mm; OverallWidth: 800 mm
Pset_WindowCommon - ThermalTransmittance: 0; GlazingAreaFraction: 0.3036
AC_Pset_RenovationAndPhasing - Renovation Status: Existing

# IfcWindow: Window 26, G120
In: TÉRREO
Type - OperationType: DOUBLE_PANEL_VERTICAL; ParameterTakesPrecedence: no; Sizeable: no
Type - Window Lining Properties - LiningDepth: 50 mm; LiningThickness: 50 mm; MullionThickness: 50 mm; FirstMullionOffset: 0.5
Type - Window Panel Properties - Panel 1 - OperationType: SLIDINGHORIZONTAL; PanelPosition: LEFT; FrameDepth: 25 mm; FrameThickness: 50 mm
Type - Window Panel Properties - Panel 2 - OperationType: FIXEDCASEMENT; PanelPosition: RIGHT; FrameDepth: 25 mm; FrameThickness: 50 mm
Description: Janela de correr com estrtutura de alumínio anodizado branco, com vidro, com peitoril em granito sienna branco com largura de 50cm; OverallHeight: 900 mm; OverallWidth: 1200 mm
Pset_WindowCommon - ThermalTransmittance: 0; GlazingAreaFraction: 0.665
AC_Pset_RenovationAndPhasing - Renovation Status: Existing

# IfcWindow: Window 26, G80
In: TÉRREO
Type - OperationType: DOUBLE_PANEL_VERTICAL; ParameterTakesPrecedence: no; Sizeable: no
Type - Window Lining Properties - LiningDepth: 50 mm; LiningThickness: 50 mm; MullionThickness: 50 mm; FirstMullionOffset: 0.5
Type - Window Panel Properties - Panel 1 - OperationType: SLIDINGHORIZONTAL; PanelPosition: RIGHT; FrameDepth: 25 mm; FrameThickness: 50 mm
Type - Window Panel Properties - Panel 2 - OperationType: FIXEDCASEMENT; PanelPosition: LEFT; FrameDepth: 25 mm; FrameThickness: 50 mm
Description: Janela de correr com estrutura de alumínio anodizado branco, com vidro, com peitoril em granito sienna branco com largura de 50cm; OverallHeight: 900 mm; OverallWidth: 800 mm
Pset_WindowCommon - ThermalTransmittance: 0; GlazingAreaFraction: 0.385
AC_Pset_RenovationAndPhasing - Renovation Status: Existing

# IfcWindow: Window 26 (5)
In: TÉRREO
Type - OperationType: SINGLE_PANEL; ParameterTakesPrecedence: no; Sizeable: no
Type - Window Lining Properties - LiningDepth: 50 mm; LiningThickness: 50 mm
Type - Window Panel Properties - Panel 1 - OperationType: FIXEDCASEMENT; PanelPosition: MIDDLE
Description: Janela de alumínio anodizado branco, abertura tipo maxim-ar, 9 folhas.; OverallHeight: 2200 mm; OverallWidth: 2200 mm
Pset_WindowCommon - ThermalTransmittance: 0; GlazingAreaFraction: 4
AC_Pset_RenovationAndPhasing - Renovation Status: Existing
